VERSION 5.7 ;
  NOWIREEXTENSIONATPIN ON ;
  DIVIDERCHAR "/" ;
  BUSBITCHARS "[]" ;
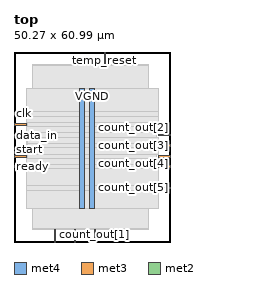
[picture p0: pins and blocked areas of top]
MACRO top
  CLASS BLOCK ;
  FOREIGN top ;
  ORIGIN 0.000 0.000 ;
  SIZE 50.270 BY 60.990 ;
  PIN VGND
    DIRECTION INOUT ;
    USE GROUND ;
    PORT
      LAYER met4 ;
        RECT 24.340 10.640 25.940 49.200 ;
    END
  END VGND
  PIN VPWR
    DIRECTION INOUT ;
    USE POWER ;
    PORT
      LAYER met4 ;
        RECT 21.040 10.640 22.640 49.200 ;
    END
  END VPWR
  PIN clk
    DIRECTION INPUT ;
    USE SIGNAL ;
    ANTENNAGATEAREA 0.852000 ;
    PORT
      LAYER met3 ;
        RECT 0.000 40.840 4.000 41.440 ;
    END
  END clk
  PIN count_out[0]
    DIRECTION OUTPUT ;
    USE SIGNAL ;
    ANTENNADIFFAREA 0.445500 ;
    PORT
      LAYER met2 ;
        RECT 19.410 0.000 19.690 4.000 ;
    END
  END count_out[0]
  PIN count_out[1]
    DIRECTION OUTPUT ;
    USE SIGNAL ;
    ANTENNADIFFAREA 0.445500 ;
    PORT
      LAYER met2 ;
        RECT 25.850 0.000 26.130 4.000 ;
    END
  END count_out[1]
  PIN count_out[2]
    DIRECTION OUTPUT ;
    USE SIGNAL ;
    ANTENNADIFFAREA 0.445500 ;
    PORT
      LAYER met3 ;
        RECT 46.270 34.040 50.270 34.640 ;
    END
  END count_out[2]
  PIN count_out[3]
    DIRECTION OUTPUT ;
    USE SIGNAL ;
    ANTENNADIFFAREA 0.445500 ;
    PORT
      LAYER met3 ;
        RECT 46.270 30.640 50.270 31.240 ;
    END
  END count_out[3]
  PIN count_out[4]
    DIRECTION OUTPUT ;
    USE SIGNAL ;
    ANTENNADIFFAREA 0.445500 ;
    PORT
      LAYER met3 ;
        RECT 46.270 27.240 50.270 27.840 ;
    END
  END count_out[4]
  PIN count_out[5]
    DIRECTION OUTPUT ;
    USE SIGNAL ;
    ANTENNADIFFAREA 0.445500 ;
    PORT
      LAYER met3 ;
        RECT 46.270 17.040 50.270 17.640 ;
    END
  END count_out[5]
  PIN count_out[6]
    DIRECTION OUTPUT ;
    USE SIGNAL ;
    ANTENNADIFFAREA 0.445500 ;
    PORT
      LAYER met3 ;
        RECT 46.270 23.840 50.270 24.440 ;
    END
  END count_out[6]
  PIN data_in
    DIRECTION INPUT ;
    USE SIGNAL ;
    ANTENNAGATEAREA 0.196500 ;
    PORT
      LAYER met3 ;
        RECT 0.000 34.040 4.000 34.640 ;
    END
  END data_in
  PIN ready
    DIRECTION OUTPUT ;
    USE SIGNAL ;
    ANTENNADIFFAREA 0.445500 ;
    PORT
      LAYER met3 ;
        RECT 0.000 23.840 4.000 24.440 ;
    END
  END ready
  PIN rst
    DIRECTION INPUT ;
    USE SIGNAL ;
    ANTENNAGATEAREA 0.213000 ;
    PORT
      LAYER met3 ;
        RECT 0.000 37.440 4.000 38.040 ;
    END
  END rst
  PIN running
    DIRECTION OUTPUT ;
    USE SIGNAL ;
    ANTENNADIFFAREA 0.445500 ;
    PORT
      LAYER met2 ;
        RECT 12.970 0.000 13.250 4.000 ;
    END
  END running
  PIN start
    DIRECTION INPUT ;
    USE SIGNAL ;
    ANTENNAGATEAREA 0.196500 ;
    PORT
      LAYER met3 ;
        RECT 0.000 27.240 4.000 27.840 ;
    END
  END start
  PIN temp_reset
    DIRECTION OUTPUT ;
    USE SIGNAL ;
    ANTENNADIFFAREA 0.795200 ;
    PORT
      LAYER met2 ;
        RECT 29.070 56.990 29.350 60.990 ;
    END
  END temp_reset
  OBS
      LAYER li1 ;
        RECT 5.520 10.795 44.620 49.045 ;
      LAYER met1 ;
        RECT 5.520 10.640 44.620 49.200 ;
      LAYER met2 ;
        RECT 6.070 56.710 28.790 56.990 ;
        RECT 29.630 56.710 43.140 56.990 ;
        RECT 6.070 4.280 43.140 56.710 ;
        RECT 6.070 4.000 12.690 4.280 ;
        RECT 13.530 4.000 19.130 4.280 ;
        RECT 19.970 4.000 25.570 4.280 ;
        RECT 26.410 4.000 43.140 4.280 ;
      LAYER met3 ;
        RECT 3.950 41.840 46.270 49.125 ;
        RECT 4.400 40.440 46.270 41.840 ;
        RECT 3.950 38.440 46.270 40.440 ;
        RECT 4.400 37.040 46.270 38.440 ;
        RECT 3.950 35.040 46.270 37.040 ;
        RECT 4.400 33.640 45.870 35.040 ;
        RECT 3.950 31.640 46.270 33.640 ;
        RECT 3.950 30.240 45.870 31.640 ;
        RECT 3.950 28.240 46.270 30.240 ;
        RECT 4.400 26.840 45.870 28.240 ;
        RECT 3.950 24.840 46.270 26.840 ;
        RECT 4.400 23.440 45.870 24.840 ;
        RECT 3.950 18.040 46.270 23.440 ;
        RECT 3.950 16.640 45.870 18.040 ;
        RECT 3.950 10.715 46.270 16.640 ;
      LAYER met4 ;
        RECT 3.975 31.455 4.305 34.505 ;
  END
END top
END LIBRARY

